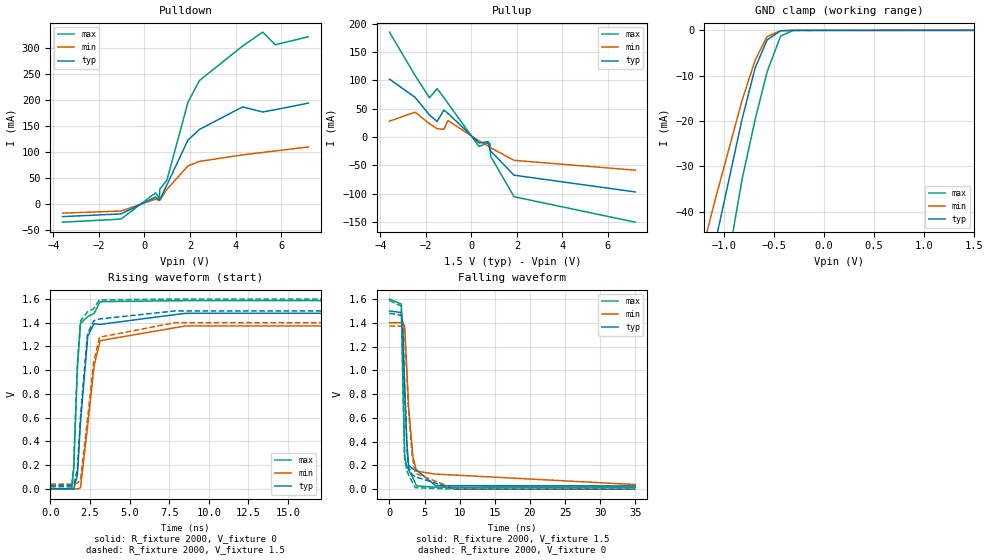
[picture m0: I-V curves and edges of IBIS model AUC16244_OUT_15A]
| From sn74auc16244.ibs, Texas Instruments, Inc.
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[Model]   AUC16244_OUT_15A
Model_type  3-state
Enable   Active-Low
Vref =   0
Rref =   2000
Cref =   15p
Vmeas =   0.75
| variable   typ   min   max
C_comp   5.56pF   4.99pF   5.82pF
| C_pullup   4.87pF   0.17pF   12.46pF
| C_pulldown   6.28pF   5.37pF   9.81pF
| C_tri-state   5.56pF   4.99pF   5.82pF
[Temperature Range]   40   100   -40
| Ambient temperature   25   85   -40
[Voltage range]   1.5   1.4   1.6
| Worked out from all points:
|   slope of the pulldown table from 0 to 0.225 V, typ, clamps not added: 37.2 ohm
|   slope of the pullup table from 0 to 0.225 V, typ, clamps not added: 30 ohm
|   GND clamp passes 1 mA (typ) near -0.53 V on its own axis
|   rising waveform, R_fixture 2000, V_fixture 0: 20-80 % time 452ps typ, 638ps min, 289ps max; typ from 0 V to 1.48 V
|   falling waveform, R_fixture 2000, V_fixture 1.5: 20-80 % time 555ps typ, 868ps min, 321ps max; typ from 1.5 V to 0.027 V
|   rising waveform, R_fixture 2000, V_fixture 1.5: 20-80 % time 447ps typ, 633ps min, 287ps max; typ from 0.027 V to 1.5 V
|   falling waveform, R_fixture 2000, V_fixture 0: 20-80 % time 553ps typ, 862ps min, 317ps max; typ from 1.48 V to 0 V
[GND Clamp]
| AUC16244_OUT_15A
|   Voltage   I(typ)   I(min)   I(max)
-3.6V     -322.9mA   -271.3mA   -392.8mA
-1.475V   -88.59mA   -71.54mA   -117.9mA
-1.34V    -73.92mA   -59.41mA   -100.2mA
-1.3V     -69.59mA   -55.85mA   -94.97mA
-1.135V   -51.9mA    -41.38mA   -73.31mA
-1.085V   -46.6mA    -37.08mA   -66.75mA
-820mV    -19.61mA   -15.47mA   -32.88mA
-690mV    -8.335mA   -6.605mA   -19.75mA
-570mV    -2.107mA   -1.378mA   -9.166mA
-435mV    -119.4uA   -67.96uA   -1.249mA
-310mV    -3.104uA   -3.774uA   -25uA
1.5V      550.3pA    9.378nA    545.2pA
[Pulldown]
| AUC16244_OUT_15A
|   Voltage   I(typ)   I(min)   I(max)
-3.6V     -23.87mA   -17.26mA   -34.61mA
-1.03V    -18.71mA   -13.15mA   -28.63mA
485mV     13.68mA    9.737mA    21.72mA
660mV     8.179mA    6.953mA    10.96mA
670mV     8.319mA    7.1mA      28.79mA
985mV     36.88mA    28.41mA    46.12mA
1.91V     123.2mA    73.57mA    195.6mA
2.415V    143.6mA    82.17mA    237.7mA
4.315V    187mA      94.84mA    304mA
5.195V    177.1mA    99.4mA     330.7mA
5.745V    181.6mA    102.3mA    306.4mA
7.2V      194.3mA    110mA      321.7mA
[Pullup]
| AUC16244_OUT_15A
|   Voltage   I(typ)   I(min)   I(max)
-3.6V     102.1mA    27.92mA    184.9mA
-2.475V   70.01mA    43.77mA    108.5mA
-1.84V    38.84mA    23.47mA    69.11mA
-1.505V   27.39mA    14.66mA    85.19mA
-1.21V    47.39mA    13.5mA     69.72mA
-1.025V   41.71mA    29.01mA    59.25mA
330mV     -10.46mA   -6.758mA   -16.68mA
740mV     -8.272mA   -15.76mA   -10.25mA
820mV     -23.65mA   -18mA      -11.49mA
845mV     -24.61mA   -18.86mA   -33.67mA
1.875V    -67.28mA   -41.09mA   -105.2mA
7.2V      -96.75mA   -58.41mA   -150.1mA
[Ramp]
| AUC16244_OUT_15A
| variable   typ   min   max
dV/dt_r   0.89/4.65E-10   0.83/6.51E-10   0.96/3.00E-10
dV/dt_f   0.88/5.76E-10   0.82/9.08E-10   0.95/3.22E-10
R_load = 2000
[Rising Waveform]
| AUC16244_OUT_15A
R_fixture =   2000
C_fixture =   0
L_fixture =   0
V_fixture =   0
V_fixture_min = 0
V_fixture_max = 0
|   Time   V(typ)   V(min)   V(max)
0s        8.895nV    33.88nV    950.2pV
1.35ns    -1.956mV   -1.596mV   -4.417mV
1.475ns   -3.029mV   -3.225mV   158.4mV
1.71ns    112.9mV    -2.46mV    1.018V
1.905ns   557.9mV    7.468mV    1.394V
2.365ns   1.288V     538.8mV    1.452V
2.765ns   1.392V     1.036V     1.479V
3.14ns    1.386V     1.249V     1.578V
8.525ns   1.48V      1.373V     1.587V
34.99ns   1.481V     1.373V     1.587V
[Falling Waveform]
| AUC16244_OUT_15A
R_fixture =   2000
C_fixture =   0
L_fixture =   0
V_fixture =   1.5
V_fixture_min = 1.4
V_fixture_max = 1.6
|   Time   V(typ)   V(min)   V(max)
0s        1.5V       1.4V       1.6V
1.695ns   1.486V     1.402V     1.558V
1.875ns   1.4V       1.4V       1.02V
2.165ns   869.1mV    1.371V     278.3mV
2.495ns   375.1mV    977.7mV    186.2mV
2.725ns   202.3mV    692.5mV    161.6mV
3.34ns    168.5mV    274.3mV    95.84mV
3.855ns   161.8mV    151mV      27.37mV
6.565ns   29.52mV    127.1mV    16.57mV
34.99ns   27.21mV    38.76mV    16.42mV
[Rising Waveform]
| AUC16244_OUT_15A
R_fixture =   2000
C_fixture =   0
L_fixture =   0
V_fixture =   1.5
V_fixture_min = 1.4
V_fixture_max = 1.6
|   Time   V(typ)   V(min)   V(max)
0s        27.17mV    38.75mV    16.4mV
1.35ns    28.49mV    38.2mV     15.17mV
1.475ns   29.44mV    37.68mV    191.4mV
1.71ns    165mV      46.24mV    1.053V
1.905ns   611.6mV    73.84mV    1.415V
2.345ns   1.306V     582.1mV    1.492V
2.735ns   1.417V     1.067V     1.518V
3.105ns   1.432V     1.278V     1.593V
7.88ns    1.5V       1.401V     1.6V
34.99ns   1.5V       1.4V       1.6V
[Falling Waveform]
| AUC16244_OUT_15A
R_fixture =   2000
C_fixture =   0
L_fixture =   0
V_fixture =   0
V_fixture_min = 0
V_fixture_max = 0
|   Time   V(typ)   V(min)   V(max)
0s        1.481V     1.373V     1.587V
1.695ns   1.462V     1.371V     1.541V
1.875ns   1.372V     1.367V     1.008V
2.165ns   848.8mV    1.331V     255.7mV
2.465ns   380.9mV    983mV      157.4mV
2.685ns   193.2mV    694.1mV    126.4mV
3.22ns    122.7mV    291.8mV    63.3mV
3.675ns   104.2mV    134.5mV    12.44mV
9.345ns   298.2uV    2.443mV    98.17uV
34.99ns   41.87uV    6.841uV    17.44uV
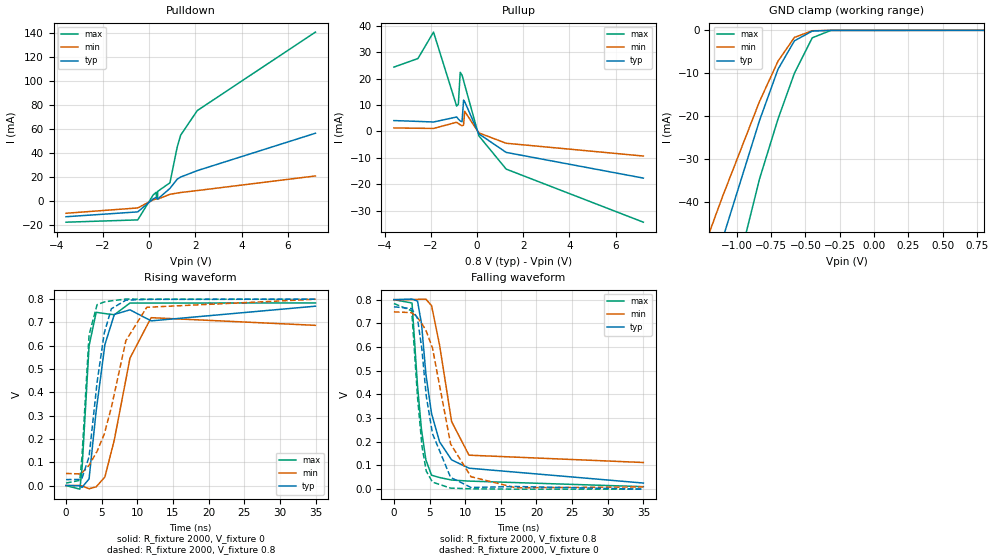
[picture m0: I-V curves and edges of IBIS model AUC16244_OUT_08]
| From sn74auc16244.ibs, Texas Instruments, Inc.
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[Model]   AUC16244_OUT_08
Model_type  3-state
Enable   Active-Low
Vref =   0
Rref =   2000
Cref =   15p
Vmeas =   0.4
| variable   typ   min   max
C_comp   5.77pF   5.27pF   6.01pF
| C_pullup   5.89pF   1.41pF   8.24pF
| C_pulldown   6.39pF   5.81pF   6.83pF
| C_tri-state   5.77pF   5.27pF   6.01pF
[Temperature Range]   40   100   -40
| Ambient temperature   25   85   -40
[Voltage range]   0.8   0.8   0.8
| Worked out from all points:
|   slope of the pulldown table from 0 to 0.12 V, typ, clamps not added: 77.5 ohm
|   slope of the pullup table from 0 to 0.12 V, typ, clamps not added: 92.7 ohm
|   GND clamp passes 1 mA (typ) near -0.53 V on its own axis
|   rising waveform, R_fixture 2000, V_fixture 0: 20-80 % time 1.8ns typ, 2.56ns min, 926ps max; typ from 0 V to 0.77 V
|   falling waveform, R_fixture 2000, V_fixture 0.8: 20-80 % time 2.68ns typ, 2.31ns min, 1.37ns max; typ from 0.8 V to 0.026 V
|   rising waveform, R_fixture 2000, V_fixture 0.8: 20-80 % time 1.84ns typ, 3.62ns min, 895ps max; typ from 0.025 V to 0.8 V
|   falling waveform, R_fixture 2000, V_fixture 0: 20-80 % time 2.28ns typ, 2.97ns min, 1.24ns max; typ from 0.77 V to 0 V
[GND Clamp]
| AUC16244_OUT_08
|   Voltage   I(typ)   I(min)   I(max)
-3.6V     -322.9mA   -271.3mA   -392.8mA
-1.495V   -90.78mA   -73.35mA   -120.5mA
-1.455V   -86.41mA   -69.74mA   -115.3mA
-1.31V    -70.67mA   -56.74mA   -96.28mA
-1.14V    -52.43mA   -41.81mA   -73.96mA
-1.1V     -48.18mA   -38.36mA   -68.71mA
-835mV    -21.05mA   -16.6mA    -34.66mA
-700mV    -9.08mA    -7.201mA   -20.67mA
-580mV    -2.442mA   -1.648mA   -9.983mA
-450mV    -176.5uA   -96.06uA   -1.735mA
-315mV    -3.617uA   -4.295uA   -30.24uA
800mV     320.2pA    582.4pA    244.4pA
[Pulldown]
| AUC16244_OUT_08
|   Voltage   I(typ)   I(min)   I(max)
-3.6V     -12.84mA   -9.953mA   -17.38mA
-495mV    -8.803mA   -5.523mA   -15.47mA
175mV     2.059mA    1.185mA    5.31mA
310mV     3.174mA    2.053mA    7.502mA
315mV     3.217mA    2.087mA    2.47mA
365mV     1.856mA    1.796mA    2.807mA
370mV     1.894mA    1.829mA    8.27mA
900mV     10.72mA    5.829mA    15.4mA
1.215V    18.4mA     6.852mA    45.18mA
1.365V    20.2mA     7.318mA    55.07mA
2.085V    25.54mA    8.939mA    75.52mA
7.2V      56.65mA    21.1mA     140.8mA
[Pullup]
| AUC16244_OUT_08
|   Voltage   I(typ)   I(min)   I(max)
-3.6V     4.13mA     1.333mA    24.36mA
-2.56V    3.817mA    1.227mA    27.6mA
-1.885V   3.587mA    1.149mA    37.6mA
-885mV    5.478mA    3.491mA    9.6mA
-810mV    4.708mA    3.016mA    10.3mA
-730mV    3.982mA    2.544mA    22.37mA
-650mV    3.702mA    2.149mA    21.3mA
-585mV    11.85mA    2.417mA    19.32mA
-535mV    11.24mA    7.608mA    17.64mA
75mV      -881.4uA   -518.8uA   -1.613mA
1.26V     -7.908mA   -4.45mA    -14.23mA
7.2V      -17.63mA   -9.285mA   -34.31mA
[Ramp]
| AUC16244_OUT_08
| variable   typ   min   max
dV/dt_r   0.47/1.86E-09   0.46/3.12E-09   0.48/9.77E-10
dV/dt_f   0.47/2.73E-09   0.42/2.36E-09   0.47/1.38E-09
R_load = 2000
[Rising Waveform]
| AUC16244_OUT_08
R_fixture =   2000
C_fixture =   0
L_fixture =   0
V_fixture =   0
V_fixture_min = 0
V_fixture_max = 0
|   Time   V(typ)   V(min)   V(max)
0s        10.26nV    58.84nV    576.2pV
1.945ns   -1.117mV   208.5uV    -15.59mV
2.25ns    -7.996mV   -1.761mV   72.96mV
3.235ns   28.43mV    -13.88mV   599.5mV
4.235ns   320.9mV    -5.419mV   743.6mV
5.46ns    605.6mV    36.82mV    738.2mV
6.78ns    734.5mV    196.3mV    733.3mV
8.975ns   754.3mV    547mV      783.5mV
11.94ns   706.9mV    720.6mV    783.5mV
34.99ns   769.9mV    687.7mV    783.7mV
[Falling Waveform]
| AUC16244_OUT_08
R_fixture =   2000
C_fixture =   0
L_fixture =   0
V_fixture =   0.8
V_fixture_min = 0.8
V_fixture_max = 0.8
|   Time   V(typ)   V(min)   V(max)
0s        800mV      800mV      800mV
2.54ns    802.6mV    800.5mV    786mV
3.31ns    794.1mV    801.4mV    436.3mV
3.875ns   697.6mV    802.1mV    249.1mV
4.49ns    484.8mV    802mV      122.9mV
5.28ns    319.2mV    774.9mV    58.94mV
6.405ns   199.8mV    608.4mV    49.21mV
8.09ns    123.7mV    285.6mV    38.57mV
10.53ns   88.61mV    143.5mV    34.1mV
34.99ns   25.83mV    112.6mV    10.63mV
[Rising Waveform]
| AUC16244_OUT_08
R_fixture =   2000
C_fixture =   0
L_fixture =   0
V_fixture =   0.8
V_fixture_min = 0.8
V_fixture_max = 0.8
|   Time   V(typ)   V(min)   V(max)
0s        25.46mV    51.93mV    10.6mV
1.93ns    26.16mV    49.79mV    21.98mV
2.235ns   30.88mV    54.1mV     120.1mV
3.235ns   123.3mV    87.06mV    646.6mV
4.36ns    442.7mV    146.6mV    776.4mV
5.365ns   654.8mV    220.8mV    788.1mV
6.365ns   758.8mV    335.4mV    792.9mV
8.395ns   795.7mV    621.8mV    800.5mV
11.33ns   799mV      765.2mV    799.8mV
34.99ns   799.9mV    799.6mV    800mV
[Falling Waveform]
| AUC16244_OUT_08
R_fixture =   2000
C_fixture =   0
L_fixture =   0
V_fixture =   0
V_fixture_min = 0
V_fixture_max = 0
|   Time   V(typ)   V(min)   V(max)
0s        770mV      748.6mV    783.8mV
2.5ns     762.3mV    745.2mV    753.1mV
3.305ns   721.1mV    724.1mV    391.2mV
3.94ns    586.3mV    698.2mV    181mV
4.535ns   392.7mV    667.1mV    76.41mV
5.41ns    234.2mV    596.1mV    29.7mV
7.955ns   49.38mV    190.8mV    4.474mV
10.82ns   7.207mV    52.49mV    1.467mV
17.05ns   11.18mV    5.889mV    82.5uV
34.99ns   136.9uV    9.402mV    28.94uV
